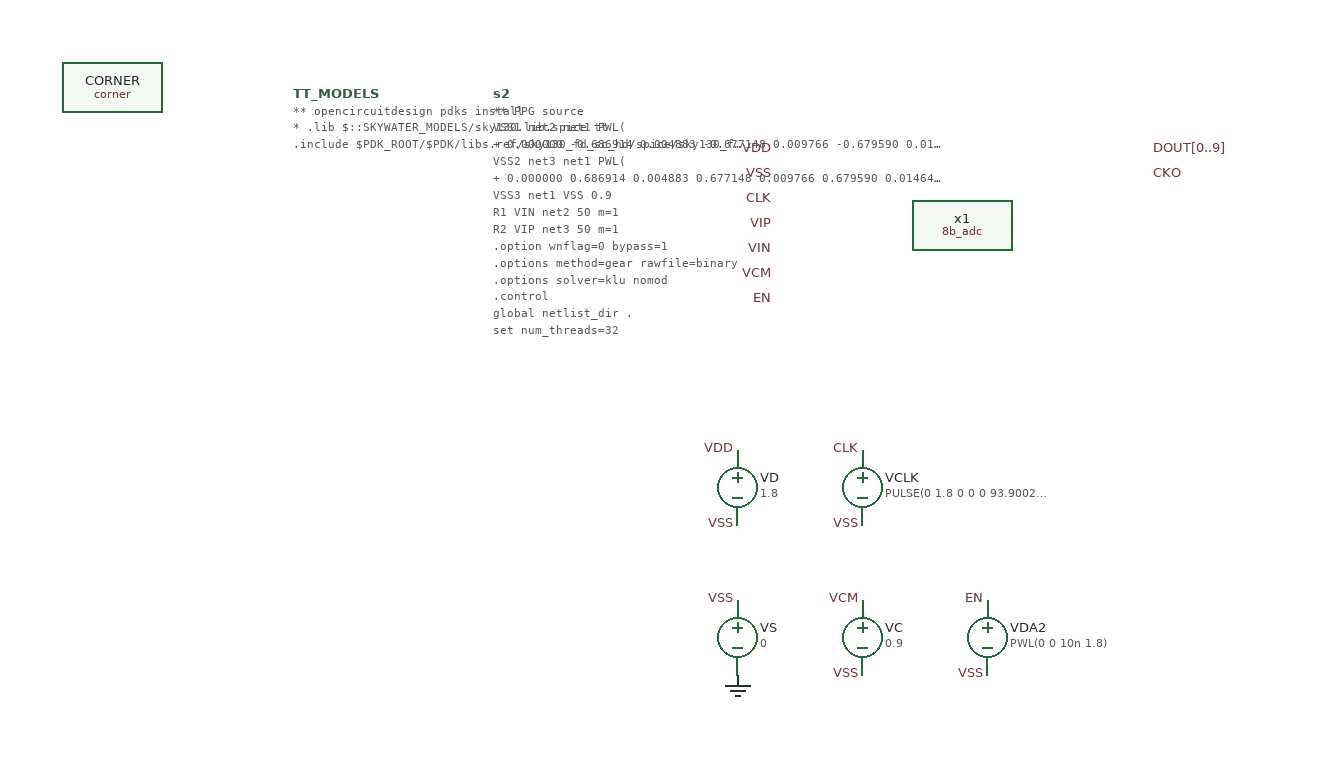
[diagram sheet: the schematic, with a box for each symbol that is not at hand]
v {xschem version=3.4.6 file_version=1.2}
G {}
K {}
V {}
S {}
E {}
B 2 1000 -480 1800 -80 {flags=graph
y1=-0.81257287
y2=2.0580623
ypos1=0
ypos2=2
divy=5
subdivy=1
unity=1
x1=-0.0023191372
x2=0.0098548111
divx=5
subdivx=1
xlabmag=1.0
ylabmag=1.0


dataset=-1
unitx=1
logx=0
logy=0


hilight_wave=0
color="18 6 11 7 8"
node="x1.vcn
x1.vcp
vip
vin
vcm"}
B 2 1820 -480 2620 -80 {flags=graph
y1=0
y2=2
ypos1=0.084216068
ypos2=3.1138986
divy=5
subdivy=1
unity=1
x1=-0.0023191372
x2=0.0098548111
divx=5
subdivx=1
xlabmag=1.0
ylabmag=1.0
node="cko
clk
BUS_NAME;dout0,dout1,dout2,dout3,dout4,dout5,dout6,dout7,dout8,dout9
dout9
dout8
dout7
dout6
dout5
dout4
dout3
dout2
dout1
dout0
x1.cks
x1.cksb"
color="4 4 4 4 4 4 4 4 4 4 4 4 4 4 4"
dataset=-1
unitx=1
logx=0
logy=0
hilight_wave=0
digital=1
sim_type=tran
autoload=0}
C {devices/vsource.sym} 540 -130 0 0 {name=VS value=0 savecurrent=false}
C {devices/vsource.sym} 540 -250 0 0 {name=VD value=1.8 savecurrent=false}
C {devices/gnd.sym} 540 -100 0 0 {name=l1 lab=GND}
C {devices/lab_wire.sym} 540 -160 0 0 {name=p1 sig_type=std_logic lab=VSS}
C {devices/lab_wire.sym} 540 -220 2 1 {name=p2 sig_type=std_logic lab=VSS}
C {devices/lab_wire.sym} 570 -500 0 0 {name=p6 sig_type=std_logic lab=VSS}
C {devices/lab_wire.sym} 540 -280 0 0 {name=p7 sig_type=std_logic lab=VDD}
C {devices/lab_wire.sym} 570 -520 0 0 {name=p8 sig_type=std_logic lab=VDD}
C {devices/lab_wire.sym} 570 -480 0 0 {name=p12 sig_type=std_logic lab=CLK}
C {devices/lab_wire.sym} 570 -460 0 0 {name=p18 sig_type=std_logic lab=VIP}
C {devices/lab_wire.sym} 570 -440 0 0 {name=p19 sig_type=std_logic lab=VIN}
C {devices/lab_wire.sym} 870 -520 0 1 {name=p21 sig_type=std_logic lab=DOUT[0..9]}
C {devices/lab_wire.sym} 870 -500 0 1 {name=p22 sig_type=std_logic lab=CKO}
C {devices/code.sym} 185 -565 0 0 {name=TT_MODELS
only_toplevel=true
format="tcleval( @value )"
value="
** opencircuitdesign pdks install
* .lib $::SKYWATER_MODELS/sky130.lib.spice tt
.include $PDK_ROOT/$PDK/libs.ref/sky130_fd_sc_hd/spice/sky130_fd_sc_hd.spice
"
spice_ignore=false}
C {devices/code.sym} 345 -565 0 0 {name=s2 only_toplevel=false value="
** PPG source
VSS1 net2 net1 PWL(
+ 0.000000 -0.686914 0.004883 -0.677148 0.009766 -0.679590 0.014648 -0.682031 0.019531 -0.691797 0.024414 -0.684473 0.029297 -0.684473 0.034180 -0.691797 0.039063 -0.699121 0.043945 -0.696680 0.048828 -0.696680 0.053711 -0.704004 0.058594 -0.711328 0.063477 -0.711328 0.068359 -0.711328 0.073242 -0.718652 0.078125 -0.721094 0.083008 -0.721094 0.087891 -0.721094 0.092773 -0.728418 0.097656 -0.733301 0.102539 -0.733301 0.107422 -0.730859 0.112305 -0.735742 0.117188 -0.740625 0.122070 -0.740625 0.126953 -0.735742 0.131836 -0.740625 0.136719 -0.743066 0.141602 -0.743066 0.146484 -0.738184 0.151367 -0.740625 0.156250 -0.743066 0.161133 -0.745508 0.166016 -0.733301 0.170899 -0.738184 0.175781 -0.738184 0.180664 -0.740625 0.185547 -0.733301 0.190430 -0.733301 0.195313 -0.733301 0.200195 -0.738184 0.205078 -0.728418 0.209961 -0.728418 0.214844 -0.728418 0.219727 -0.733301 0.224609 -0.723535 0.229492 -0.723535 0.234375 -0.725977 0.239258 -0.730859 0.244141 -0.721094 0.249024 -0.721094 0.253906 -0.721094 0.258789 -0.725977 0.263672 -0.718652 0.268555 -0.716211 0.273438 -0.718652 0.278320 -0.721094 0.283203 -0.718652 0.288086 -0.713770 0.292969 -0.718652 0.297852 -0.721094 0.302734 -0.718652 0.307617 -0.713770 0.312500 -0.716211 0.317383 -0.721094 0.322266 -0.718652 0.327149 -0.711328 0.332031 -0.716211 0.336914 -0.718652 0.341797 -0.718652 0.346680 -0.713770 0.351563 -0.716211 0.356445 -0.718652 0.361328 -0.718652 0.366211 -0.711328 0.371094 -0.716211 0.375977 -0.718652 0.380859 -0.721094 0.385742 -0.711328 0.390625 -0.713770 0.395508 -0.716211 0.400391 -0.721094 0.405274 -0.711328 0.410156 -0.716211 0.415039 -0.718652 0.419922 -0.723535 0.424805 -0.713770 0.429688 -0.718652 0.434570 -0.721094 0.439453 -0.728418 0.444336 -0.723535 0.449219 -0.725977 0.454102 -0.733301 0.458984 -0.745508 0.463867 -0.740625 0.468750 -0.747949 0.473633 -0.755273 0.478516 -0.769922 0.483399 -0.769922 0.488281 -0.777246 0.493164 -0.789453 0.498047 -0.801660 0.502930 -0.804102 0.507813 -0.806543 0.512695 -0.816309 0.517578 -0.826074 0.522461 -0.826074 0.527344 -0.823633 0.532227 -0.828516 0.537109 -0.833398 0.541992 -0.833398 0.546875 -0.826074 0.551758 -0.826074 0.556641 -0.826074 0.561523 -0.821191 0.566406 -0.811426 0.571289 -0.808984 0.576172 -0.806543 0.581055 -0.801660 0.585938 -0.787012 0.590820 -0.784570 0.595703 -0.777246 0.600586 -0.772363 0.605469 -0.755273 0.610352 -0.752832 0.615234 -0.745508 0.620117 -0.743066 0.625000 -0.728418 0.629883 -0.723535 0.634766 -0.721094 0.639648 -0.718652 0.644531 -0.706445 0.649414 -0.704004 0.654297 -0.701562 0.659180 -0.701562 0.664063 -0.689355 0.668945 -0.686914 0.673828 -0.686914 0.678711 -0.691797 0.683594 -0.682031 0.688477 -0.682031 0.693359 -0.682031 )
VSS2 net3 net1 PWL(
+ 0.000000 0.686914 0.004883 0.677148 0.009766 0.679590 0.014648 0.682031 0.019531 0.691797 0.024414 0.684473 0.029297 0.684473 0.034180 0.691797 0.039063 0.699121 0.043945 0.696680 0.048828 0.696680 0.053711 0.704004 0.058594 0.711328 0.063477 0.711328 0.068359 0.711328 0.073242 0.718652 0.078125 0.721094 0.083008 0.721094 0.087891 0.721094 0.092773 0.728418 0.097656 0.733301 0.102539 0.733301 0.107422 0.730859 0.112305 0.735742 0.117188 0.740625 0.122070 0.740625 0.126953 0.735742 0.131836 0.740625 0.136719 0.743066 0.141602 0.743066 0.146484 0.738184 0.151367 0.740625 0.156250 0.743066 0.161133 0.745508 0.166016 0.733301 0.170899 0.738184 0.175781 0.738184 0.180664 0.740625 0.185547 0.733301 0.190430 0.733301 0.195313 0.733301 0.200195 0.738184 0.205078 0.728418 0.209961 0.728418 0.214844 0.728418 0.219727 0.733301 0.224609 0.723535 0.229492 0.723535 0.234375 0.725977 0.239258 0.730859 0.244141 0.721094 0.249024 0.721094 0.253906 0.721094 0.258789 0.725977 0.263672 0.718652 0.268555 0.716211 0.273438 0.718652 0.278320 0.721094 0.283203 0.718652 0.288086 0.713770 0.292969 0.718652 0.297852 0.721094 0.302734 0.718652 0.307617 0.713770 0.312500 0.716211 0.317383 0.721094 0.322266 0.718652 0.327149 0.711328 0.332031 0.716211 0.336914 0.718652 0.341797 0.718652 0.346680 0.713770 0.351563 0.716211 0.356445 0.718652 0.361328 0.718652 0.366211 0.711328 0.371094 0.716211 0.375977 0.718652 0.380859 0.721094 0.385742 0.711328 0.390625 0.713770 0.395508 0.716211 0.400391 0.721094 0.405274 0.711328 0.410156 0.716211 0.415039 0.718652 0.419922 0.723535 0.424805 0.713770 0.429688 0.718652 0.434570 0.721094 0.439453 0.728418 0.444336 0.723535 0.449219 0.725977 0.454102 0.733301 0.458984 0.745508 0.463867 0.740625 0.468750 0.747949 0.473633 0.755273 0.478516 0.769922 0.483399 0.769922 0.488281 0.777246 0.493164 0.789453 0.498047 0.801660 0.502930 0.804102 0.507813 0.806543 0.512695 0.816309 0.517578 0.826074 0.522461 0.826074 0.527344 0.823633 0.532227 0.828516 0.537109 0.833398 0.541992 0.833398 0.546875 0.826074 0.551758 0.826074 0.556641 0.826074 0.561523 0.821191 0.566406 0.811426 0.571289 0.808984 0.576172 0.806543 0.581055 0.801660 0.585938 0.787012 0.590820 0.784570 0.595703 0.777246 0.600586 0.772363 0.605469 0.755273 0.610352 0.752832 0.615234 0.745508 0.620117 0.743066 0.625000 0.728418 0.629883 0.723535 0.634766 0.721094 0.639648 0.718652 0.644531 0.706445 0.649414 0.704004 0.654297 0.701562 0.659180 0.701562 0.664063 0.689355 0.668945 0.686914 0.673828 0.686914 0.678711 0.691797 0.683594 0.682031 0.688477 0.682031 0.693359 0.682031 )
VSS3 net1 VSS 0.9
R1 VIN net2 50 m=1
R2 VIP net3 50 m=1

.option wnflag=0 bypass=1
.options method=gear rawfile=binary
.options solver=klu nomod  
.control  
global netlist_dir .  
set num_threads=32
set wr_singlescale
save x1.vcp x1.vcn vip vin clk vcm cko x1.cks x1.cksb vdd i(vd)
+ dout0 dout1 dout2 dout3 dout4 dout5 dout6 dout7 dout8 dout9
tran 1u 700m 0 0.1u uic ; Mengubah start time menjadi 10n
rusage traniter trantime
let pow = -i(vd)*vdd
meas tran inst_pow MAX pow from=1n to=535u
meas tran avg_pow  AVG pow from=1n to=535u
remzerovec  
write adc10b_tb_ppg.raw  
wrdata adc10b_tb_ppg.txt cko dout0 dout1 dout2 dout3 dout4 dout5 dout6 dout7 dout8 dout9 pow
quit 1
.endc
"}
C {devices/vsource.sym} 640 -250 0 0 {name=VCLK value="PULSE(0 1.8 0 0 0 93.9002403846154u 187.8004807692308u)" savecurrent=false}
C {devices/lab_wire.sym} 640 -280 0 0 {name=p23 sig_type=std_logic lab=CLK}
C {devices/lab_wire.sym} 640 -220 2 1 {name=p24 sig_type=std_logic lab=VSS}
C {sky130_fd_pr/corner.sym} 40 -570 0 0 {name=CORNER only_toplevel=false corner=tt}
C {devices/launcher.sym} 1060 -520 0 0 {name=h5
descr="load waves" 
tclcommand="xschem raw_read $netlist_dir/adc10b_tb_ppg.raw tran"
}
C {8b_adc.sym} 720 -460 0 0 {name=x1}
C {devices/lab_wire.sym} 570 -420 0 0 {name=p4 sig_type=std_logic lab=VCM}
C {devices/vsource.sym} 640 -130 0 0 {name=VC value=0.9 savecurrent=false}
C {devices/lab_wire.sym} 640 -100 2 1 {name=p5 sig_type=std_logic lab=VSS}
C {devices/lab_wire.sym} 640 -160 0 0 {name=p9 sig_type=std_logic lab=VCM}
C {devices/lab_wire.sym} 570 -400 0 0 {name=p10 sig_type=std_logic lab=EN}
C {devices/vsource.sym} 740 -130 0 0 {name=VDA2 value="PWL(0 0 10n 1.8)" savecurrent=false}
C {devices/lab_wire.sym} 740 -100 2 1 {name=p11 sig_type=std_logic lab=VSS}
C {devices/lab_wire.sym} 740 -160 0 0 {name=p13 sig_type=std_logic lab=EN}
